VERSION 5.7 ;
  NOWIREEXTENSIONATPIN ON ;
  DIVIDERCHAR "/" ;
  BUSBITCHARS "[]" ;
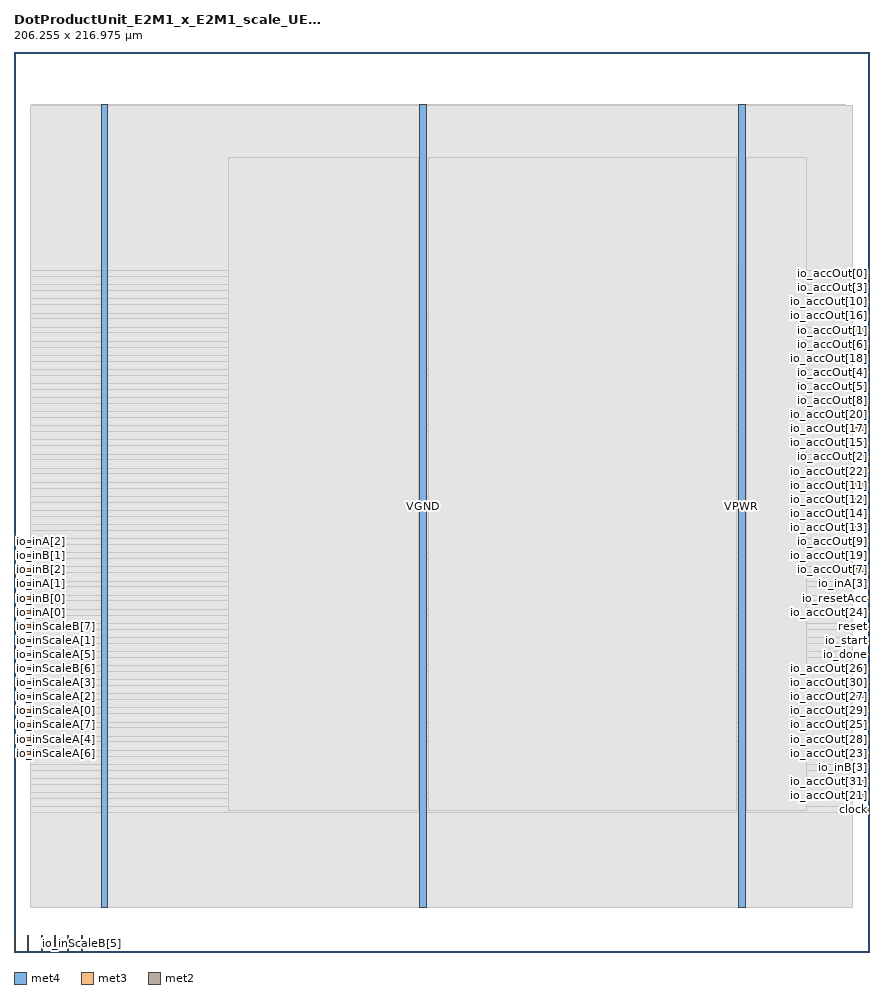
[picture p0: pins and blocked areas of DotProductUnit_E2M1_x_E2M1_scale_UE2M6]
MACRO DotProductUnit_E2M1_x_E2M1_scale_UE2M6
  CLASS BLOCK ;
  FOREIGN DotProductUnit_E2M1_x_E2M1_scale_UE2M6 ;
  ORIGIN 0.000 0.000 ;
  SIZE 206.255 BY 216.975 ;
  PIN VGND
    DIRECTION INOUT ;
    USE GROUND ;
    PORT
      LAYER met4 ;
        RECT 97.840 10.640 99.440 204.240 ;
    END
  END VGND
  PIN VPWR
    DIRECTION INOUT ;
    USE POWER ;
    PORT
      LAYER met4 ;
        RECT 21.040 10.640 22.640 204.240 ;
    END
    PORT
      LAYER met4 ;
        RECT 174.640 10.640 176.240 204.240 ;
    END
  END VPWR
  PIN clock
    DIRECTION INPUT ;
    USE SIGNAL ;
    ANTENNAGATEAREA 0.852000 ;
    PORT
      LAYER met3 ;
        RECT 202.255 34.040 206.255 34.640 ;
    END
  END clock
  PIN io_accOut[0]
    DIRECTION OUTPUT ;
    USE SIGNAL ;
    ANTENNADIFFAREA 0.445500 ;
    PORT
      LAYER met3 ;
        RECT 202.255 163.240 206.255 163.840 ;
    END
  END io_accOut[0]
  PIN io_accOut[10]
    DIRECTION OUTPUT ;
    USE SIGNAL ;
    ANTENNADIFFAREA 0.445500 ;
    PORT
      LAYER met3 ;
        RECT 202.255 156.440 206.255 157.040 ;
    END
  END io_accOut[10]
  PIN io_accOut[11]
    DIRECTION OUTPUT ;
    USE SIGNAL ;
    ANTENNADIFFAREA 0.445500 ;
    PORT
      LAYER met3 ;
        RECT 202.255 112.240 206.255 112.840 ;
    END
  END io_accOut[11]
  PIN io_accOut[12]
    DIRECTION OUTPUT ;
    USE SIGNAL ;
    ANTENNADIFFAREA 0.445500 ;
    PORT
      LAYER met3 ;
        RECT 202.255 108.840 206.255 109.440 ;
    END
  END io_accOut[12]
  PIN io_accOut[13]
    DIRECTION OUTPUT ;
    USE SIGNAL ;
    ANTENNADIFFAREA 0.445500 ;
    PORT
      LAYER met3 ;
        RECT 202.255 102.040 206.255 102.640 ;
    END
  END io_accOut[13]
  PIN io_accOut[14]
    DIRECTION OUTPUT ;
    USE SIGNAL ;
    ANTENNADIFFAREA 0.445500 ;
    PORT
      LAYER met3 ;
        RECT 202.255 105.440 206.255 106.040 ;
    END
  END io_accOut[14]
  PIN io_accOut[15]
    DIRECTION OUTPUT ;
    USE SIGNAL ;
    ANTENNADIFFAREA 0.445500 ;
    PORT
      LAYER met3 ;
        RECT 202.255 122.440 206.255 123.040 ;
    END
  END io_accOut[15]
  PIN io_accOut[16]
    DIRECTION OUTPUT ;
    USE SIGNAL ;
    ANTENNADIFFAREA 0.445500 ;
    PORT
      LAYER met3 ;
        RECT 202.255 153.040 206.255 153.640 ;
    END
  END io_accOut[16]
  PIN io_accOut[17]
    DIRECTION OUTPUT ;
    USE SIGNAL ;
    ANTENNADIFFAREA 0.445500 ;
    PORT
      LAYER met3 ;
        RECT 202.255 125.840 206.255 126.440 ;
    END
  END io_accOut[17]
  PIN io_accOut[18]
    DIRECTION OUTPUT ;
    USE SIGNAL ;
    ANTENNADIFFAREA 0.445500 ;
    PORT
      LAYER met3 ;
        RECT 202.255 142.840 206.255 143.440 ;
    END
  END io_accOut[18]
  PIN io_accOut[19]
    DIRECTION OUTPUT ;
    USE SIGNAL ;
    ANTENNADIFFAREA 0.445500 ;
    PORT
      LAYER met3 ;
        RECT 202.255 95.240 206.255 95.840 ;
    END
  END io_accOut[19]
  PIN io_accOut[1]
    DIRECTION OUTPUT ;
    USE SIGNAL ;
    ANTENNADIFFAREA 0.445500 ;
    PORT
      LAYER met3 ;
        RECT 202.255 149.640 206.255 150.240 ;
    END
  END io_accOut[1]
  PIN io_accOut[20]
    DIRECTION OUTPUT ;
    USE SIGNAL ;
    ANTENNADIFFAREA 0.445500 ;
    PORT
      LAYER met3 ;
        RECT 202.255 129.240 206.255 129.840 ;
    END
  END io_accOut[20]
  PIN io_accOut[21]
    DIRECTION OUTPUT ;
    USE SIGNAL ;
    ANTENNADIFFAREA 0.445500 ;
    PORT
      LAYER met3 ;
        RECT 202.255 37.440 206.255 38.040 ;
    END
  END io_accOut[21]
  PIN io_accOut[22]
    DIRECTION OUTPUT ;
    USE SIGNAL ;
    ANTENNADIFFAREA 0.445500 ;
    PORT
      LAYER met3 ;
        RECT 202.255 115.640 206.255 116.240 ;
    END
  END io_accOut[22]
  PIN io_accOut[23]
    DIRECTION OUTPUT ;
    USE SIGNAL ;
    ANTENNADIFFAREA 0.445500 ;
    PORT
      LAYER met3 ;
        RECT 202.255 47.640 206.255 48.240 ;
    END
  END io_accOut[23]
  PIN io_accOut[24]
    DIRECTION OUTPUT ;
    USE SIGNAL ;
    ANTENNADIFFAREA 0.445500 ;
    PORT
      LAYER met3 ;
        RECT 202.255 81.640 206.255 82.240 ;
    END
  END io_accOut[24]
  PIN io_accOut[25]
    DIRECTION OUTPUT ;
    USE SIGNAL ;
    ANTENNADIFFAREA 0.445500 ;
    PORT
      LAYER met3 ;
        RECT 202.255 54.440 206.255 55.040 ;
    END
  END io_accOut[25]
  PIN io_accOut[26]
    DIRECTION OUTPUT ;
    USE SIGNAL ;
    ANTENNADIFFAREA 0.445500 ;
    PORT
      LAYER met3 ;
        RECT 202.255 68.040 206.255 68.640 ;
    END
  END io_accOut[26]
  PIN io_accOut[27]
    DIRECTION OUTPUT ;
    USE SIGNAL ;
    ANTENNADIFFAREA 0.445500 ;
    PORT
      LAYER met3 ;
        RECT 202.255 61.240 206.255 61.840 ;
    END
  END io_accOut[27]
  PIN io_accOut[28]
    DIRECTION OUTPUT ;
    USE SIGNAL ;
    ANTENNADIFFAREA 0.445500 ;
    PORT
      LAYER met3 ;
        RECT 202.255 51.040 206.255 51.640 ;
    END
  END io_accOut[28]
  PIN io_accOut[29]
    DIRECTION OUTPUT ;
    USE SIGNAL ;
    ANTENNADIFFAREA 0.445500 ;
    PORT
      LAYER met3 ;
        RECT 202.255 57.840 206.255 58.440 ;
    END
  END io_accOut[29]
  PIN io_accOut[2]
    DIRECTION OUTPUT ;
    USE SIGNAL ;
    ANTENNADIFFAREA 0.445500 ;
    PORT
      LAYER met3 ;
        RECT 202.255 119.040 206.255 119.640 ;
    END
  END io_accOut[2]
  PIN io_accOut[30]
    DIRECTION OUTPUT ;
    USE SIGNAL ;
    ANTENNADIFFAREA 0.445500 ;
    PORT
      LAYER met3 ;
        RECT 202.255 64.640 206.255 65.240 ;
    END
  END io_accOut[30]
  PIN io_accOut[31]
    DIRECTION OUTPUT ;
    USE SIGNAL ;
    ANTENNADIFFAREA 0.445500 ;
    PORT
      LAYER met3 ;
        RECT 202.255 40.840 206.255 41.440 ;
    END
  END io_accOut[31]
  PIN io_accOut[3]
    DIRECTION OUTPUT ;
    USE SIGNAL ;
    ANTENNADIFFAREA 0.445500 ;
    PORT
      LAYER met3 ;
        RECT 202.255 159.840 206.255 160.440 ;
    END
  END io_accOut[3]
  PIN io_accOut[4]
    DIRECTION OUTPUT ;
    USE SIGNAL ;
    ANTENNADIFFAREA 0.445500 ;
    PORT
      LAYER met3 ;
        RECT 202.255 139.440 206.255 140.040 ;
    END
  END io_accOut[4]
  PIN io_accOut[5]
    DIRECTION OUTPUT ;
    USE SIGNAL ;
    ANTENNADIFFAREA 0.445500 ;
    PORT
      LAYER met3 ;
        RECT 202.255 136.040 206.255 136.640 ;
    END
  END io_accOut[5]
  PIN io_accOut[6]
    DIRECTION OUTPUT ;
    USE SIGNAL ;
    ANTENNADIFFAREA 0.445500 ;
    PORT
      LAYER met3 ;
        RECT 202.255 146.240 206.255 146.840 ;
    END
  END io_accOut[6]
  PIN io_accOut[7]
    DIRECTION OUTPUT ;
    USE SIGNAL ;
    ANTENNADIFFAREA 0.445500 ;
    PORT
      LAYER met3 ;
        RECT 202.255 91.840 206.255 92.440 ;
    END
  END io_accOut[7]
  PIN io_accOut[8]
    DIRECTION OUTPUT ;
    USE SIGNAL ;
    ANTENNADIFFAREA 0.445500 ;
    PORT
      LAYER met3 ;
        RECT 202.255 132.640 206.255 133.240 ;
    END
  END io_accOut[8]
  PIN io_accOut[9]
    DIRECTION OUTPUT ;
    USE SIGNAL ;
    ANTENNADIFFAREA 0.445500 ;
    PORT
      LAYER met3 ;
        RECT 202.255 98.640 206.255 99.240 ;
    END
  END io_accOut[9]
  PIN io_done
    DIRECTION OUTPUT ;
    USE SIGNAL ;
    ANTENNADIFFAREA 0.445500 ;
    PORT
      LAYER met3 ;
        RECT 202.255 71.440 206.255 72.040 ;
    END
  END io_done
  PIN io_inA[0]
    DIRECTION INPUT ;
    USE SIGNAL ;
    ANTENNAGATEAREA 0.196500 ;
    PORT
      LAYER met3 ;
        RECT 0.000 81.640 4.000 82.240 ;
    END
  END io_inA[0]
  PIN io_inA[1]
    DIRECTION INPUT ;
    USE SIGNAL ;
    ANTENNAGATEAREA 0.196500 ;
    PORT
      LAYER met3 ;
        RECT 0.000 88.440 4.000 89.040 ;
    END
  END io_inA[1]
  PIN io_inA[2]
    DIRECTION INPUT ;
    USE SIGNAL ;
    ANTENNAGATEAREA 0.196500 ;
    PORT
      LAYER met3 ;
        RECT 0.000 98.640 4.000 99.240 ;
    END
  END io_inA[2]
  PIN io_inA[3]
    DIRECTION INPUT ;
    USE SIGNAL ;
    ANTENNAGATEAREA 0.196500 ;
    PORT
      LAYER met3 ;
        RECT 202.255 88.440 206.255 89.040 ;
    END
  END io_inA[3]
  PIN io_inB[0]
    DIRECTION INPUT ;
    USE SIGNAL ;
    ANTENNAGATEAREA 0.196500 ;
    PORT
      LAYER met3 ;
        RECT 0.000 85.040 4.000 85.640 ;
    END
  END io_inB[0]
  PIN io_inB[1]
    DIRECTION INPUT ;
    USE SIGNAL ;
    ANTENNAGATEAREA 0.126000 ;
    PORT
      LAYER met3 ;
        RECT 0.000 95.240 4.000 95.840 ;
    END
  END io_inB[1]
  PIN io_inB[2]
    DIRECTION INPUT ;
    USE SIGNAL ;
    ANTENNAGATEAREA 0.126000 ;
    PORT
      LAYER met3 ;
        RECT 0.000 91.840 4.000 92.440 ;
    END
  END io_inB[2]
  PIN io_inB[3]
    DIRECTION INPUT ;
    USE SIGNAL ;
    ANTENNAGATEAREA 0.196500 ;
    PORT
      LAYER met3 ;
        RECT 202.255 44.240 206.255 44.840 ;
    END
  END io_inB[3]
  PIN io_inScaleA[0]
    DIRECTION INPUT ;
    USE SIGNAL ;
    ANTENNAGATEAREA 0.213000 ;
    PORT
      LAYER met3 ;
        RECT 0.000 57.840 4.000 58.440 ;
    END
  END io_inScaleA[0]
  PIN io_inScaleA[1]
    DIRECTION INPUT ;
    USE SIGNAL ;
    ANTENNAGATEAREA 0.196500 ;
    PORT
      LAYER met3 ;
        RECT 0.000 74.840 4.000 75.440 ;
    END
  END io_inScaleA[1]
  PIN io_inScaleA[2]
    DIRECTION INPUT ;
    USE SIGNAL ;
    ANTENNAGATEAREA 0.196500 ;
    PORT
      LAYER met3 ;
        RECT 0.000 61.240 4.000 61.840 ;
    END
  END io_inScaleA[2]
  PIN io_inScaleA[3]
    DIRECTION INPUT ;
    USE SIGNAL ;
    ANTENNAGATEAREA 0.196500 ;
    PORT
      LAYER met3 ;
        RECT 0.000 64.640 4.000 65.240 ;
    END
  END io_inScaleA[3]
  PIN io_inScaleA[4]
    DIRECTION INPUT ;
    USE SIGNAL ;
    ANTENNAGATEAREA 0.247500 ;
    PORT
      LAYER met3 ;
        RECT 0.000 51.040 4.000 51.640 ;
    END
  END io_inScaleA[4]
  PIN io_inScaleA[5]
    DIRECTION INPUT ;
    USE SIGNAL ;
    ANTENNAGATEAREA 0.196500 ;
    PORT
      LAYER met3 ;
        RECT 0.000 71.440 4.000 72.040 ;
    END
  END io_inScaleA[5]
  PIN io_inScaleA[6]
    DIRECTION INPUT ;
    USE SIGNAL ;
    ANTENNAGATEAREA 0.495000 ;
    PORT
      LAYER met3 ;
        RECT 0.000 47.640 4.000 48.240 ;
    END
  END io_inScaleA[6]
  PIN io_inScaleA[7]
    DIRECTION INPUT ;
    USE SIGNAL ;
    ANTENNAGATEAREA 0.495000 ;
    PORT
      LAYER met3 ;
        RECT 0.000 54.440 4.000 55.040 ;
    END
  END io_inScaleA[7]
  PIN io_inScaleB[0]
    DIRECTION INPUT ;
    USE SIGNAL ;
    PORT
      LAYER met2 ;
        RECT 0.090 0.000 0.370 4.000 ;
    END
  END io_inScaleB[0]
  PIN io_inScaleB[1]
    DIRECTION INPUT ;
    USE SIGNAL ;
    PORT
      LAYER met2 ;
        RECT 3.310 0.000 3.590 4.000 ;
    END
  END io_inScaleB[1]
  PIN io_inScaleB[2]
    DIRECTION INPUT ;
    USE SIGNAL ;
    PORT
      LAYER met2 ;
        RECT 6.530 0.000 6.810 4.000 ;
    END
  END io_inScaleB[2]
  PIN io_inScaleB[3]
    DIRECTION INPUT ;
    USE SIGNAL ;
    PORT
      LAYER met2 ;
        RECT 9.750 0.000 10.030 4.000 ;
    END
  END io_inScaleB[3]
  PIN io_inScaleB[4]
    DIRECTION INPUT ;
    USE SIGNAL ;
    PORT
      LAYER met2 ;
        RECT 12.970 0.000 13.250 4.000 ;
    END
  END io_inScaleB[4]
  PIN io_inScaleB[5]
    DIRECTION INPUT ;
    USE SIGNAL ;
    PORT
      LAYER met2 ;
        RECT 16.190 0.000 16.470 4.000 ;
    END
  END io_inScaleB[5]
  PIN io_inScaleB[6]
    DIRECTION INPUT ;
    USE SIGNAL ;
    ANTENNAGATEAREA 0.196500 ;
    PORT
      LAYER met3 ;
        RECT 0.000 68.040 4.000 68.640 ;
    END
  END io_inScaleB[6]
  PIN io_inScaleB[7]
    DIRECTION INPUT ;
    USE SIGNAL ;
    ANTENNAGATEAREA 0.196500 ;
    PORT
      LAYER met3 ;
        RECT 0.000 78.240 4.000 78.840 ;
    END
  END io_inScaleB[7]
  PIN io_resetAcc
    DIRECTION INPUT ;
    USE SIGNAL ;
    ANTENNAGATEAREA 0.196500 ;
    PORT
      LAYER met3 ;
        RECT 202.255 85.040 206.255 85.640 ;
    END
  END io_resetAcc
  PIN io_start
    DIRECTION INPUT ;
    USE SIGNAL ;
    ANTENNAGATEAREA 0.196500 ;
    PORT
      LAYER met3 ;
        RECT 202.255 74.840 206.255 75.440 ;
    END
  END io_start
  PIN reset
    DIRECTION INPUT ;
    USE SIGNAL ;
    ANTENNAGATEAREA 0.196500 ;
    PORT
      LAYER met3 ;
        RECT 202.255 78.240 206.255 78.840 ;
    END
  END reset
  OBS
      LAYER nwell ;
        RECT 5.330 10.795 200.750 204.190 ;
      LAYER li1 ;
        RECT 5.520 10.795 200.560 204.085 ;
      LAYER met1 ;
        RECT 4.210 10.640 200.560 204.240 ;
      LAYER met2 ;
        RECT 4.230 10.695 199.090 204.185 ;
      LAYER met3 ;
        RECT 3.990 164.240 202.255 204.165 ;
        RECT 3.990 162.840 201.855 164.240 ;
        RECT 3.990 160.840 202.255 162.840 ;
        RECT 3.990 159.440 201.855 160.840 ;
        RECT 3.990 157.440 202.255 159.440 ;
        RECT 3.990 156.040 201.855 157.440 ;
        RECT 3.990 154.040 202.255 156.040 ;
        RECT 3.990 152.640 201.855 154.040 ;
        RECT 3.990 150.640 202.255 152.640 ;
        RECT 3.990 149.240 201.855 150.640 ;
        RECT 3.990 147.240 202.255 149.240 ;
        RECT 3.990 145.840 201.855 147.240 ;
        RECT 3.990 143.840 202.255 145.840 ;
        RECT 3.990 142.440 201.855 143.840 ;
        RECT 3.990 140.440 202.255 142.440 ;
        RECT 3.990 139.040 201.855 140.440 ;
        RECT 3.990 137.040 202.255 139.040 ;
        RECT 3.990 135.640 201.855 137.040 ;
        RECT 3.990 133.640 202.255 135.640 ;
        RECT 3.990 132.240 201.855 133.640 ;
        RECT 3.990 130.240 202.255 132.240 ;
        RECT 3.990 128.840 201.855 130.240 ;
        RECT 3.990 126.840 202.255 128.840 ;
        RECT 3.990 125.440 201.855 126.840 ;
        RECT 3.990 123.440 202.255 125.440 ;
        RECT 3.990 122.040 201.855 123.440 ;
        RECT 3.990 120.040 202.255 122.040 ;
        RECT 3.990 118.640 201.855 120.040 ;
        RECT 3.990 116.640 202.255 118.640 ;
        RECT 3.990 115.240 201.855 116.640 ;
        RECT 3.990 113.240 202.255 115.240 ;
        RECT 3.990 111.840 201.855 113.240 ;
        RECT 3.990 109.840 202.255 111.840 ;
        RECT 3.990 108.440 201.855 109.840 ;
        RECT 3.990 106.440 202.255 108.440 ;
        RECT 3.990 105.040 201.855 106.440 ;
        RECT 3.990 103.040 202.255 105.040 ;
        RECT 3.990 101.640 201.855 103.040 ;
        RECT 3.990 99.640 202.255 101.640 ;
        RECT 4.400 98.240 201.855 99.640 ;
        RECT 3.990 96.240 202.255 98.240 ;
        RECT 4.400 94.840 201.855 96.240 ;
        RECT 3.990 92.840 202.255 94.840 ;
        RECT 4.400 91.440 201.855 92.840 ;
        RECT 3.990 89.440 202.255 91.440 ;
        RECT 4.400 88.040 201.855 89.440 ;
        RECT 3.990 86.040 202.255 88.040 ;
        RECT 4.400 84.640 201.855 86.040 ;
        RECT 3.990 82.640 202.255 84.640 ;
        RECT 4.400 81.240 201.855 82.640 ;
        RECT 3.990 79.240 202.255 81.240 ;
        RECT 4.400 77.840 201.855 79.240 ;
        RECT 3.990 75.840 202.255 77.840 ;
        RECT 4.400 74.440 201.855 75.840 ;
        RECT 3.990 72.440 202.255 74.440 ;
        RECT 4.400 71.040 201.855 72.440 ;
        RECT 3.990 69.040 202.255 71.040 ;
        RECT 4.400 67.640 201.855 69.040 ;
        RECT 3.990 65.640 202.255 67.640 ;
        RECT 4.400 64.240 201.855 65.640 ;
        RECT 3.990 62.240 202.255 64.240 ;
        RECT 4.400 60.840 201.855 62.240 ;
        RECT 3.990 58.840 202.255 60.840 ;
        RECT 4.400 57.440 201.855 58.840 ;
        RECT 3.990 55.440 202.255 57.440 ;
        RECT 4.400 54.040 201.855 55.440 ;
        RECT 3.990 52.040 202.255 54.040 ;
        RECT 4.400 50.640 201.855 52.040 ;
        RECT 3.990 48.640 202.255 50.640 ;
        RECT 4.400 47.240 201.855 48.640 ;
        RECT 3.990 45.240 202.255 47.240 ;
        RECT 3.990 43.840 201.855 45.240 ;
        RECT 3.990 41.840 202.255 43.840 ;
        RECT 3.990 40.440 201.855 41.840 ;
        RECT 3.990 38.440 202.255 40.440 ;
        RECT 3.990 37.040 201.855 38.440 ;
        RECT 3.990 35.040 202.255 37.040 ;
        RECT 3.990 33.640 201.855 35.040 ;
        RECT 3.990 10.715 202.255 33.640 ;
      LAYER met4 ;
        RECT 51.815 34.175 97.440 191.585 ;
        RECT 99.840 34.175 174.240 191.585 ;
        RECT 176.640 34.175 191.065 191.585 ;
  END
END DotProductUnit_E2M1_x_E2M1_scale_UE2M6
END LIBRARY

